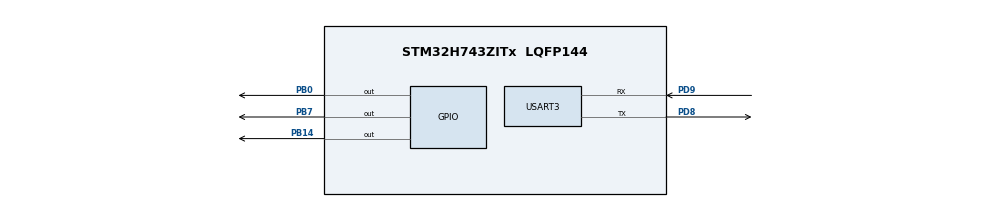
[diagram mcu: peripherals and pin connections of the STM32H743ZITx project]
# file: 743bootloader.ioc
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CORTEX_M7.CPU_DCache=Enabled
CORTEX_M7.CPU_ICache=Enabled
Dma.Request0=USART3_RX
Dma.Request1=USART3_TX
Dma.USART3_RX.0.Direction=DMA_PERIPH_TO_MEMORY
Dma.USART3_RX.0.EventEnable=DISABLE
Dma.USART3_RX.0.FIFOMode=DMA_FIFOMODE_DISABLE
Dma.USART3_RX.0.Instance=DMA1_Stream0
Dma.USART3_RX.0.MemDataAlignment=DMA_MDATAALIGN_BYTE
Dma.USART3_RX.0.MemInc=DMA_MINC_ENABLE
Dma.USART3_RX.0.Mode=DMA_NORMAL
Dma.USART3_RX.0.PeriphDataAlignment=DMA_PDATAALIGN_BYTE
Dma.USART3_RX.0.PeriphInc=DMA_PINC_DISABLE
Dma.USART3_RX.0.Polarity=HAL_DMAMUX_REQ_GEN_RISING
Dma.USART3_RX.0.Priority=DMA_PRIORITY_LOW
Dma.USART3_RX.0.RequestNumber=1
Dma.USART3_RX.0.SignalID=NONE
Dma.USART3_RX.0.SyncEnable=DISABLE
Dma.USART3_RX.0.SyncPolarity=HAL_DMAMUX_SYNC_NO_EVENT
Dma.USART3_RX.0.SyncRequestNumber=1
Dma.USART3_RX.0.SyncSignalID=NONE
Dma.USART3_TX.1.Direction=DMA_MEMORY_TO_PERIPH
Dma.USART3_TX.1.EventEnable=DISABLE
Dma.USART3_TX.1.FIFOMode=DMA_FIFOMODE_DISABLE
Dma.USART3_TX.1.Instance=DMA1_Stream1
Dma.USART3_TX.1.MemDataAlignment=DMA_MDATAALIGN_BYTE
Dma.USART3_TX.1.MemInc=DMA_MINC_ENABLE
Dma.USART3_TX.1.Mode=DMA_NORMAL
Dma.USART3_TX.1.PeriphDataAlignment=DMA_PDATAALIGN_BYTE
Dma.USART3_TX.1.PeriphInc=DMA_PINC_DISABLE
Dma.USART3_TX.1.Polarity=HAL_DMAMUX_REQ_GEN_RISING
Dma.USART3_TX.1.Priority=DMA_PRIORITY_LOW
Dma.USART3_TX.1.RequestNumber=1
Dma.USART3_TX.1.SignalID=NONE
Dma.USART3_TX.1.SyncEnable=DISABLE
Dma.USART3_TX.1.SyncPolarity=HAL_DMAMUX_SYNC_NO_EVENT
Dma.USART3_TX.1.SyncRequestNumber=1
Dma.USART3_TX.1.SyncSignalID=NONE
Mcu.Family=STM32H7
Mcu.Name=STM32H743ZITx
Mcu.Package=LQFP144
NVIC.DMA1_Stream0_IRQn=true\:0\:0\:false\:false\:true\:false\:true
NVIC.DMA1_Stream1_IRQn=true\:0\:0\:false\:false\:true\:false\:true
NVIC.PriorityGroup=NVIC_PRIORITYGROUP_4
NVIC.TIM2_IRQn=true\:0\:0\:false\:false\:true\:true\:true
NVIC.USART3_IRQn=true\:0\:0\:false\:false\:true\:true\:true
PB0.Signal=GPIO_Output
PB14.Signal=GPIO_Output
PB7.Signal=GPIO_Output
PC14-OSC32_IN\ (OSC32_IN).Mode=LSE-External-Oscillator
PC14-OSC32_IN\ (OSC32_IN).Signal=RCC_OSC32_IN
PC15-OSC32_OUT\ (OSC32_OUT).Mode=LSE-External-Oscillator
PC15-OSC32_OUT\ (OSC32_OUT).Signal=RCC_OSC32_OUT
PD8.Mode=Asynchronous
PD8.Signal=USART3_TX
PD9.Mode=Asynchronous
PD9.Signal=USART3_RX
PH0-OSC_IN\ (PH0).Mode=HSE-External-Oscillator
PH0-OSC_IN\ (PH0).Signal=RCC_OSC_IN
PH1-OSC_OUT\ (PH1).Mode=HSE-External-Oscillator
PH1-OSC_OUT\ (PH1).Signal=RCC_OSC_OUT
ProjectManager.HeapSize=0x200
ProjectManager.StackSize=0x400
ProjectManager.TargetToolchain=MDK-ARM V5
RCC.ADCFreq_Value=16125000
RCC.APB1Freq_Value=12500000
RCC.APB2Freq_Value=12500000
RCC.APB3Freq_Value=12500000
RCC.APB4Freq_Value=12500000
RCC.CortexFreq_Value=50000000
RCC.Cortex_Div=SYSTICK_CLKSOURCE_HCLK_DIV8
RCC.D1PPRE=RCC_APB3_DIV2
RCC.D2PPRE1=RCC_APB1_DIV2
RCC.D2PPRE2=RCC_APB2_DIV2
RCC.D3PPRE=RCC_APB4_DIV2
RCC.DIVM1=1
RCC.DIVN1=100
RCC.FLatency=FLASH_LATENCY_2
RCC.HCLKFreq_Value=25000000
RCC.HPRE=RCC_HCLK_DIV16
RCC.HSE_VALUE=8000000
RCC.PLLSourceVirtual=RCC_PLLSOURCE_HSE
RCC.PWR_Regulator_Voltage_Scale=PWR_REGULATOR_VOLTAGE_SCALE1
RCC.SYSCLKFreq_VALUE=400000000
RCC.SYSCLKSource=RCC_SYSCLKSOURCE_PLLCLK
RCC.USBFreq_Value=400000000
TIM2.AutoReloadPreload=TIM_AUTORELOAD_PRELOAD_ENABLE
TIM2.Period=0xffffFFFF
TIM2.Prescaler=30
USART3.VirtualMode-Asynchronous=VM_ASYNC
VP_TIM2_VS_ClockSourceINT.Mode=Internal
board=custom

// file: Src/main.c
/* USER CODE BEGIN Header */
/**
  ******************************************************************************
  * @file           : main.c
  * @brief          : Main program body
  ******************************************************************************
  * @attention
  *
  * <h2><center>&copy; Copyright (c) 2019 STMicroelectronics.
  * All rights reserved.</center></h2>
  *
  * This software component is licensed by ST under BSD 3-Clause license,
  * the "License"; You may not use this file except in compliance with the
  * License. You may obtain a copy of the License at:
  *                        opensource.org/licenses/BSD-3-Clause
  *
  ******************************************************************************
  */
/* USER CODE END Header */

#include "main.h"
#include "dma.h"
#include "tim.h"
#include "usart.h"
#include "gpio.h"

/* USER CODE BEGIN Includes */
#include "stdio.h"
#include "string.h"
#include "led.h"
#include "math.h"
#include "stm32_hal_legacy.h"
#include "stm32h7xx_hal_def.h"
#include "arm_math.h"

/* USER CODE END Includes */

/* USER CODE BEGIN PD */
//#define APPLICATION_ADDRESS   (uint32_t)0x8000000
//#if (defined ( __CC_ARM ))
//  uint32_t   * const VectorTable = (uint32_t *)0x24000000;
////__IO uint32_t VectorTable[48] __attribute__((at(0x24000000)));
////__attribute__((at(0x24000000))) __IO uint32_t VectorTable[48];
//#elif (defined (__ICCARM__))
//#pragma location = 0x20000000
//__no_init __IO uint32_t VectorTable[48];
//#elif defined ( __GNUC__ )
//__IO uint32_t VectorTable[48] __attribute__((section(".RAMVectorTable")));
//#endif
/* USER CODE END PD */

void SystemClock_Config(void);

int main(void)
{
  /* USER CODE BEGIN 1 */
//  for( uint8_t i=0;i<48;i++)
//  {
//      VectorTable[i] = *(  uint32_t*)(APPLICATION_ADDRESS + (i<<2));
//  }
//  __SYSCFG_CLK_ENABLE();
//   MODIFY_REG(SYSCFG->CFGR1, SYSCFG_CFGR1_MEM_MODE, (SYSCFG_CFGR1_MEM_MODE_1|SYSCFG_CFGR1_MEM_MODE_0))

//  __HAL_REMAPMEMORY_SRAM();

  /* USER CODE END 1 */

  /* Enable I-Cache---------------------------------------------------------*/
  SCB_EnableICache();

  /* Enable D-Cache---------------------------------------------------------*/
  SCB_EnableDCache();

  /* MCU Configuration--------------------------------------------------------*/

  /* Reset of all peripherals, Initializes the Flash interface and the Systick. */
  HAL_Init();

  /* Configure the system clock */
  SystemClock_Config();

  /* Initialize all configured peripherals */
  MX_GPIO_Init();
  MX_DMA_Init();
  MX_USART3_UART_Init();
  MX_TIM2_Init();
  /* USER CODE BEGIN 2 */
      uint8_t *   a = "i am app.2\r\n";
    printf(a);
    printf("i am here : 0x%x\r\n", (uint32_t)main);
    LED2ON;
    HAL_TIM_Base_Start_IT(&htim2);
    uint8_t str[100];
		 printf("I have done 1.2 CPU clock.\r\n");
		printf("SYSCLK_Frequency is %dHZ\r\n", HAL_RCC_GetSysClockFreq());
    printf("PCLK1_Frequency is %dHZ\r\n", HAL_RCC_GetPCLK1Freq());
    printf("PCLK2_Frequency is %dHZ\r\n", HAL_RCC_GetPCLK2Freq());
    printf("HAL_RCCEx_GetD1PCLK1Freq is %dHZ\r\n", HAL_RCCEx_GetD1PCLK1Freq());
    printf("HAL_RCCEx_GetD3PCLK1Freq is %dHZ\r\n", HAL_RCCEx_GetD3PCLK1Freq());
    printf("HAL_RCC_GetHCLKFreq is %dHZ\r\n", HAL_RCC_GetHCLKFreq());
    printf("HAL_RCCEx_GetD1SysClockFreq is %dHZ\r\n", HAL_RCCEx_GetD1SysClockFreq());

    printf("SystemCoreClock is %dHZ\r\n", HAL_RCCEx_GetD1SysClockFreq());

        HAL_UART_Transmit_DMA(&huart3, str, strlen((char*)str));
  /* USER CODE END 2 */

  /* Infinite loop */
  /* USER CODE BEGIN WHILE */
    while (1)
    {
        timerStart();
        for(uint32_t i = 248000U; i--;)
        {
            sin(i);
        };
        sprintf((char*)str, "tim2 : %d\r", (uint32_t)timerStop());
        SCB_CleanInvalidateDCache();
        HAL_UART_Transmit_DMA(&huart3, str, strlen((char*)str));

    /* USER CODE END WHILE */

    }
}

void SystemClock_Config(void)
{
  RCC_OscInitTypeDef RCC_OscInitStruct = {0};
  RCC_ClkInitTypeDef RCC_ClkInitStruct = {0};
  RCC_PeriphCLKInitTypeDef PeriphClkInitStruct = {0};

  /** Supply configuration update enable
  */
  MODIFY_REG(PWR->CR3, PWR_CR3_SCUEN, 0);
  /** Configure the main internal regulator output voltage
  */
  __HAL_PWR_VOLTAGESCALING_CONFIG(PWR_REGULATOR_VOLTAGE_SCALE1);

  while ((PWR->D3CR & (PWR_D3CR_VOSRDY)) != PWR_D3CR_VOSRDY)
  {

  }
  /** Initializes the CPU, AHB and APB busses clocks
  */
  RCC_OscInitStruct.OscillatorType = RCC_OSCILLATORTYPE_HSE;
  RCC_OscInitStruct.HSEState = RCC_HSE_ON;
  RCC_OscInitStruct.PLL.PLLState = RCC_PLL_ON;
  RCC_OscInitStruct.PLL.PLLSource = RCC_PLLSOURCE_HSE;
  RCC_OscInitStruct.PLL.PLLM = 1;
  RCC_OscInitStruct.PLL.PLLN = 120;
  RCC_OscInitStruct.PLL.PLLP = 2;
  RCC_OscInitStruct.PLL.PLLQ = 2;
  RCC_OscInitStruct.PLL.PLLR = 2;
  RCC_OscInitStruct.PLL.PLLRGE = RCC_PLL1VCIRANGE_3;
  RCC_OscInitStruct.PLL.PLLVCOSEL = RCC_PLL1VCOWIDE;
  RCC_OscInitStruct.PLL.PLLFRACN = 0;
  if (HAL_RCC_OscConfig(&RCC_OscInitStruct) != HAL_OK)
  {
    Error_Handler();
  }
  /** Initializes the CPU, AHB and APB busses clocks
  */
  RCC_ClkInitStruct.ClockType = RCC_CLOCKTYPE_HCLK|RCC_CLOCKTYPE_SYSCLK
                              |RCC_CLOCKTYPE_PCLK1|RCC_CLOCKTYPE_PCLK2
                              |RCC_CLOCKTYPE_D3PCLK1|RCC_CLOCKTYPE_D1PCLK1;
  RCC_ClkInitStruct.SYSCLKSource = RCC_SYSCLKSOURCE_PLLCLK;
  RCC_ClkInitStruct.SYSCLKDivider = RCC_SYSCLK_DIV1;
  RCC_ClkInitStruct.AHBCLKDivider = RCC_HCLK_DIV16;
  RCC_ClkInitStruct.APB3CLKDivider = RCC_APB3_DIV2;
  RCC_ClkInitStruct.APB1CLKDivider = RCC_APB1_DIV2;
  RCC_ClkInitStruct.APB2CLKDivider = RCC_APB2_DIV2;
  RCC_ClkInitStruct.APB4CLKDivider = RCC_APB4_DIV2;

  if (HAL_RCC_ClockConfig(&RCC_ClkInitStruct, FLASH_LATENCY_2) != HAL_OK)
  {
    Error_Handler();
  }
  PeriphClkInitStruct.PeriphClockSelection = RCC_PERIPHCLK_USART3;
  PeriphClkInitStruct.Usart234578ClockSelection = RCC_USART234578CLKSOURCE_D2PCLK1;
  if (HAL_RCCEx_PeriphCLKConfig(&PeriphClkInitStruct) != HAL_OK)
  {
    Error_Handler();
  }
}

void Error_Handler(void)
{
}

/************************ (C) COPYRIGHT STMicroelectronics *****END OF FILE****/
